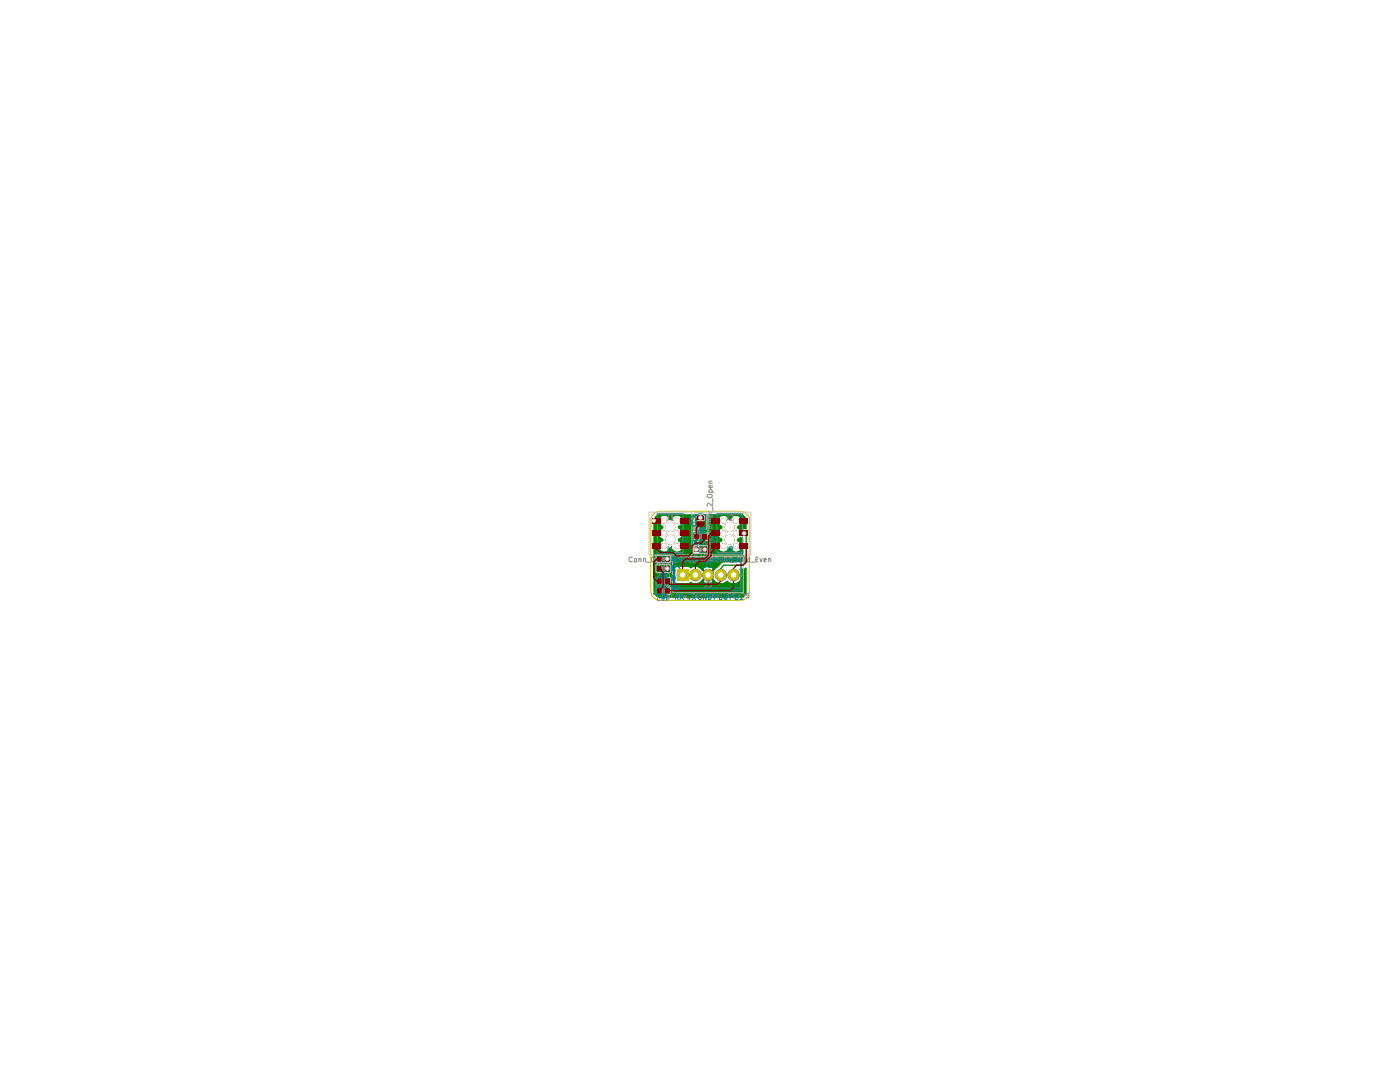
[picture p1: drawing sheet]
<svg xmlns="http://www.w3.org/2000/svg" width="279mm" height="216mm" viewBox="0 0 279 216" stroke-linecap="round" stroke-linejoin="round" font-family="sans-serif">
<g fill="none" stroke="#840084" stroke-width=".2">
<path d="M136 108.2h.5v1h-.5M136.1 108.7h.4M136.9 108.3l.3-.1 .3 .3v.5l-.3 .2-.3-.1M137.3 105.1l.2-.2 .4 .2v.6l-.4 .2a.6 .6 0 0 1-.2-.8zM137.8 109.2l.3-1 .3 1M137.9 108.9h.4M138.3 104.9h.5M138.5 104.9v1M138.7 108.2h.5v1M138.7 106.5v1M138.9 108.7h.3M139.7 107.1l-.5-.1v-.4l.5-.1v1"/>
<path d="M139.9 105.1l.2-.2 .3 .2v.6l-.2 .2-.3-.2zM140 108.7l-.4 .5M140.2 108.7h-.5l-.1-.4 .6-.1v1M140.5 107.1l-.4 .4M140.6 108.2h.5v1h-.5M140.7 107.1l-.5-.1-.1-.2 .2-.3h.4v1M140.7 108.7h.4M141.4 105l-.4-.1-.2 .2 .6 .8h-.6M141.4 108.2h.6M141.7 108.2v1M141.8 104.9v.8l.4 .2M142.3 108.2v1l.6-1v1"/>
<path d="M143.3 108.2v1"/>
</g>
<g fill="none" stroke="#840084" stroke-width=".34">
<path d="M130.5 118.4h.6M130.6 112v.1M131.1 117.6l-.3-.3v1.1M131.1 111l.6-.1a.67 .67 0 0 1 .2 .7 .67 .67 0 0 1-.5 .5l-.3-.1M131.7 118.4h.1M132.2 118.4h.6M132.4 110.9v1.2l.7-1.2v1.2M132.8 117.6l-.3-.3v1.1M133.7 110.9v1.2M134.1 117.3l.4 1.1 .4-1.1M135.1 110.9h.5l.2 .3v.6l-.2 .2h-.6v-.4h.3M135.2 117.3h.6v1.1h-.6"/>
<path d="M135.5 117.8h.3M136.3 110.9v1.2l.7-1.2v1.2M136.7 117.9l-.4 .5M137 117.9l-.6-.1-.1-.4 .2-.1h.5v1.1M137.6 110.9v1.2M138.5 111.5l-.4 .6M138.8 111.5l-.6-.1-.1-.3 .2-.2h.5v1.2M139.3 110.9h.6v1.2h-.6M139.4 117.3h-.6l-.1 .3 .7 .8h-.7M139.4 111.4h.5M139.9 117.4l.1-.1a.6 .6 0 0 1 .6 .5 .6 .6 0 0 1-.4 .6l-.3-.2zM140.4 110.9h.6v1.2h-.6"/>
<path d="M140.5 111.4h.5M141.1 118.4h.1M141.6 110.9v1.2l.6-1.2v1.2M141.6 117.6v.8M141.9 117.2l.3 .8h-.7M142.8 117.3h.4l.1 .1v.8l-.2 .2a.75 .75 0 0 1-.3-1.1zM142.8 110.9v1.2M143.3 110.9h.5l.2 .3v.6l-.2 .2h-.5v-.4h.2M143.8 118.4h.1M144.6 110.9v1.2l.7-1.2v1.2M145.1 117.3h-.6l-.1 .1v.4l.7 .6h-.7M145.8 110.9h.5v1.2h-.5"/>
<path d="M146 111.4h.3M146.2 117.3h-.6l-.1 .3 .8 .8h-.8M146.7 117.4l.2-.1a.6 .6 0 0 1 .6 .5 .6 .6 0 0 1-.4 .6l-.4-.2zM148.2 111.5l-.5 .6M148.4 111.5l-.6-.1-.1-.3 .2-.2h.5v1.2M148.5 117.3h-.6l-.1 .3 .8 .8h-.8"/>
</g>
<g fill="#848400">
<path d="M135.1 113.6h2.2v2.2h-2.2z"/>
<circle cx="138.8" cy="114.7" r="1.14"/>
<circle cx="141.3" cy="114.7" r="1.14"/>
<circle cx="143.8" cy="114.7" r="1.14"/>
<circle cx="146.4" cy="114.7" r="1.14"/>
<circle cx="133.8" cy="105.2" r=".97"/>
<circle cx="133.8" cy="107.7" r=".97"/>
<circle cx="132.5" cy="103.9" r=".55"/>
<circle cx="132.5" cy="106.4" r=".55"/>
<circle cx="132.5" cy="109" r=".55"/>
<circle cx="135" cy="103.9" r=".55"/>
<circle cx="135" cy="106.4" r=".55"/>
<circle cx="135" cy="109" r=".55"/>
<circle cx="146.9" cy="109" r=".55"/>
<circle cx="146.9" cy="106.4" r=".55"/>
<circle cx="146.9" cy="103.9" r=".55"/>
<circle cx="144.4" cy="109" r=".55"/>
<circle cx="144.4" cy="106.4" r=".55"/>
<circle cx="144.4" cy="103.9" r=".55"/>
<circle cx="145.6" cy="107.7" r=".97"/>
<circle cx="145.6" cy="105.2" r=".97"/>
</g>
<path d="M130.5 103.9h.6v6.3l2.6 2.6M133.2 113.5h.5M133.7 112.8v4.5M135 111.5l-1.3 1.3M139.8 103.3h-.4l-.5 .4v5.9M140.6 110.9h.1M140.6 109.6v1.3M140.6 110.9l-.6 .6h-6.8M141.3 114.7v1.9l-.7 .7h-9.5M148.5 106.4h.4v5.8l-.7 .6h-3.8l-.6 .7v1.2" fill="none" stroke="#008400" stroke-width=".25"/>
<path d="M130.8 103.2l.7-.5h7.5l-.5 .5-.3 .6v5.2a1.05 1.05 0 0 0 .1 1.5 1.05 1.05 0 0 0 1.4 0 1.05 1.05 0 0 0 .1-1.5l-.1-4.7h.5a1.05 1.05 0 0 0 .5-1.6h7.2l.5 .2 .3 .3 .2 .6v1.7a.92 .92 0 0 0-1.1 .3l-.6-.4 .1-.4a1.09 1.09 0 0 0 .7-1.6l-.7-.6h-.7a1.06 1.06 0 0 0-.8 .9h-.3l-.6-.8a1.16 1.16 0 0 0-1.5 .5 1.16 1.16 0 0 0 .4 1.5l.3 .1v.4a1.13 1.13 0 0 0-.9 1.1 1.13 1.13 0 0 0 .9 1.1v.3a1.17 1.17 0 0 0-.6 2 1.17 1.17 0 0 0 2-.6h.3a1.15 1.15 0 0 0 1.6 .8 1.15 1.15 0 0 0 .6-1.6l-.8-.6v-.2l.6-.5 .4 .3v4.4l-.2 .2h-3.5l-.6 .2-2.4 2.5 .8 .8a1.8 1.8 0 0 0 2.9 .3 1.74 1.74 0 0 0 2.4 .1 1.74 1.74 0 0 0 .1-2.4h.9l.3-.3v4.8a1.14 1.14 0 0 1-.9 1.1h-16.5l-.7-.5-.3-.8v-4.2h4v2.2l.2 .5 2.8 .1 .4-.3 .4 .3a1.71 1.71 0 0 0 1.7-.6h.2a1.24 1.24 0 0 0 2.2 0l-1.1-1-1.1 1h-.2l1.1-1.1-1.1-1.2h.2l1.1 1 1.1-1a1.24 1.24 0 0 0-2.2 0h-.2a1.45 1.45 0 0 0-2.1-.3l-.5-.3h-2.2l-.5 .2-.2 .5h-4v-9.7l.1-.2h.8a1.08 1.08 0 0 0 .9 1.3v.3h-.3a1.22 1.22 0 0 0-.5 1.7l.8 .6v.2l-.3 .1a1.22 1.22 0 0 0-.5 1.6 1.17 1.17 0 0 0 1.2 .6 1.17 1.17 0 0 0 .9-.9h.4a1.17 1.17 0 0 0 1.9 .6 1.17 1.17 0 0 0-.5-2v-.3a1.13 1.13 0 0 0 .9-1.1 1.13 1.13 0 0 0-.9-1.1v-.4a1.13 1.13 0 0 0 .9-1.1 1.13 1.13 0 0 0-.9-1.1h-.7l-.6 .6-.1 .3h-.4a1.06 1.06 0 0 0-.7-.9l-.9 .1-.5 .5-.1 .4h-.8z" fill="#008400"/>
<path d="M130.8 103.2l.7-.5h7.5l-.5 .5-.3 .6v5.2a1.05 1.05 0 0 0 .1 1.5 1.05 1.05 0 0 0 1.4 0 1.05 1.05 0 0 0 .1-1.5l-.1-4.7h.5a1.05 1.05 0 0 0 .5-1.6h7.2l.5 .2 .3 .3 .2 .6v1.7a.92 .92 0 0 0-1.1 .3l-.6-.4 .1-.4a1.09 1.09 0 0 0 .7-1.6l-.7-.6h-.7a1.06 1.06 0 0 0-.8 .9h-.3l-.6-.8a1.16 1.16 0 0 0-1.5 .5 1.16 1.16 0 0 0 .4 1.5l.3 .1v.4a1.13 1.13 0 0 0-.9 1.1 1.13 1.13 0 0 0 .9 1.1v.3a1.17 1.17 0 0 0-.6 2 1.17 1.17 0 0 0 2-.6h.3a1.15 1.15 0 0 0 1.6 .8 1.15 1.15 0 0 0 .6-1.6l-.8-.6v-.2l.6-.5 .4 .3v4.4l-.2 .2h-3.5l-.6 .2-2.4 2.5 .8 .8a1.8 1.8 0 0 0 2.9 .3 1.74 1.74 0 0 0 2.4 .1 1.74 1.74 0 0 0 .1-2.4h.9l.3-.3v4.8a1.14 1.14 0 0 1-.9 1.1h-16.5l-.7-.5-.3-.8v-4.2h4v2.2l.2 .5 2.8 .1 .4-.3 .4 .3a1.71 1.71 0 0 0 1.7-.6h.2a1.24 1.24 0 0 0 2.2 0l-1.1-1-1.1 1h-.2l1.1-1.1-1.1-1.2h.2l1.1 1 1.1-1a1.24 1.24 0 0 0-2.2 0h-.2a1.45 1.45 0 0 0-2.1-.3l-.5-.3h-2.2l-.5 .2-.2 .5h-4v-9.7l.1-.2h.8a1.08 1.08 0 0 0 .9 1.3v.3h-.3a1.22 1.22 0 0 0-.5 1.7l.8 .6v.2l-.3 .1a1.22 1.22 0 0 0-.5 1.6 1.17 1.17 0 0 0 1.2 .6 1.17 1.17 0 0 0 .9-.9h.4a1.17 1.17 0 0 0 1.9 .6 1.17 1.17 0 0 0-.5-2v-.3a1.13 1.13 0 0 0 .9-1.1 1.13 1.13 0 0 0-.9-1.1v-.4a1.13 1.13 0 0 0 .9-1.1 1.13 1.13 0 0 0-.9-1.1h-.7l-.6 .6-.1 .3h-.4a1.06 1.06 0 0 0-.7-.9l-.9 .1-.5 .5-.1 .4h-.8z" fill="none" stroke="#008400" stroke-width=".25"/>
<path d="M129.9 117.9a1.91 1.91 0 0 0 1.9 1.9M129.9 103.9v14M131.7 102h16M131.7 119.8h16M131.8 102a1.91 1.91 0 0 0-1.9 1.9M147.7 102a1.91 1.91 0 0 1 1.9 1.9M149.5 103.9v14M149.6 117.9a1.91 1.91 0 0 1-1.9 1.9" fill="none" stroke="#c2c200" stroke-width=".2"/>
<g fill="none" stroke="#848484" stroke-width=".2">
<path d="M141.3 98.6h.7l.2 .5a.6 .6 0 0 1-1.1 0zM141.5 98.2h1M141.5 96.4h.7M141.6 98.2l-.1-.3 .1-.2h.4l.2 .2-.1 .3M142.1 96.9l.1 .3-.2 .2h-.4l-.1-.4 .2-.1 .1 .5M142.2 96h-.6v.4M142.2 99.5v.7M126.2 111.2h-.5l-.1 .1v.6l.1 .2 .5-.1M126.6 111.6l.1-.2 .3 .1v.6l-.4-.1zM127.5 111.6l.2-.2 .2 .2v.5M127.5 111.4v.7M128.4 111.6l.1-.2 .4 .2v.5"/>
<path d="M128.4 111.4v.7M129 112.2h.8M130.1 111.2h.4l.1 .1-.1 .8h-.4l-.1-.2zM131 111.2h.5l.1 .2-.7 .7h.7M131.1 112.5l.6-.1v.3l-.6 .8h.6M131.1 114.5l.4-.2 .2 .3-.6 .7h.6M131.2 116.8v1.1h.5M131.2 118.8v1h.5M131.2 103.5l.7 .4-.7 .4M131.2 102.6h5.1v7.6h-5.1zM131.6 111.2h1.6v.7h-1.6zM131.6 113h1.6v.9h-1.6z"/>
<path d="M131.6 115.9l.3-.3h1.3v.8h-1.6zM131.6 117.8l.3-.3h1.3v.8h-1.6zM131.9 111.4l.5 .7M132.1 112.5l.5-.1 .1 .2-.6 .9h.6M132.1 114.5l.4-.2 .2 .3-.6 .7h.6M132.1 117.3h.3M132.1 119.3h.3M132.1 115.8l.3 .1-.1 .3h-.2zM132.1 117.7l.3 .1-.2 .3zM132.1 111.5h.3v-.1h-.3v.4M132.1 113.5l.3-.2-.3-.1v.5M132.2 111.5l.2 .3"/>
<path d="M132.2 113.5l.2 .2M132.4 111.4l-.5 .7M132.5 117.7h.2v.4h-.2M132.5 113.2h.2v.5h-.2M132.5 115.9l.1-.1 .1 .1-.2 .3h.2M132.5 111.4h.2v.1l-.2 .3h.2M132.6 116.8h-.5v1.1h.5M132.6 118.8h-.5v1h.5M132.8 111.2h.4l.1 .1-.1 .8h-.4v-.2zM133 116.8l.5 .3v.5l-.2 .3h-.3zM133 118.8h.3l.2 .2v.5l-.3 .3h-.2zM133.2 112.4l.4 .2v.6l-.3 .3-.3-.5z"/>
<path d="M133.2 114.4l.1-.1 .3 .3v.5l-.2 .2a.52 .52 0 0 1-.4-.4 .52 .52 0 0 1 .2-.5zM133.4 102.8v.8l-.1 .2h-.2M133.6 118.4h-.5a.36 .36 0 0 0 0 .4 .36 .36 0 0 0 .4 .1v.4h-.5M133.6 111.2h.7l-.4 .3 .4 .2-.1 .4-.6-.1M133.9 103.1l.3-.3v1M133.9 103.8h.5M134.4 118.7l-.4 .1v.4l.4 .1M134.4 112.2h.8M134.7 111.6h13.1v6.3h-12.6l-.5-.6zM134.7 112h13.1M134.7 117.3h13.1M134.9 118.7v.6"/>
<path d="M135.2 118.7h-.2l-.1 .2M135.5 119l.5-.1-.1-.2-.4 .1v.4l.4 .1M135.5 111.2h.6v.8h-.6zM136.3 118.7l.2 .6 .1-.4 .2 .4 .3-.6M136.9 111.2v.9h-.3l-.1-.5 .1-.2 .3 .1M136.9 113.9l-1.5 1.5M137 114l-1.5 1.6M137.2 119.5h.7M137.8 111.2v.9h-.4v-.6h.4M137.9 111.2h-.4l-.2 .4 .2 .5 .4-.1M138 118.4h.6M138.1 112.2h.8"/>
<path d="M138.3 111.6l.2-.2 .3 .1v.6l-.5-.1zM138.3 118.4v.9M138.7 107.9v1.1h.5M138.8 110.5l-.2 .7h.6M138.9 119l.5-.1v-.2l-.5 .1v.5h.5M139 109.2h1.6v.9h-1.6zM139 110.8v.7M139.3 111.6l.1-.2 .3 .1v.6M139.3 106.7h1.3v.8h-1.6v-.5zM139.3 111.4v.7M139.4 110.5h.7l-.4 1M139.4 113.9l-1.5 1.5"/>
<path d="M139.5 111.2h-.4v.9h.4M139.5 108.5h.3M139.5 114l-1.5 1.6M139.6 106.9l.1 .1v.3h-.1zM139.6 109.7h.1v-.3h-.1v.5M139.7 109.7v.2M139.8 118.7v.6M139.9 111.4l.2 .7 .3-.7M139.9 107.1l.2-.2v.4M139.9 109.6l.2-.2v.5M139.9 107.3h.3M139.9 109.9h.3"/>
<path d="M140 107.9h-.5v1.1h.5M140.1 118.7h-.2l-.1 .2M140.2 111.6l.1-.2 .3 .2v.5M140.2 111.4v.7M140.4 107.9a.59 .59 0 0 1 .5 .4 .59 .59 0 0 1-.1 .7h-.4zM140.4 118.8l.4-.1v.6M140.4 118.7v.6M140.5 110.7l.2-.2a.63 .63 0 0 1 .2 1l-.4-.1zM140.7 111.8l.4-.1v-.3l-.4 .1v.6h.4M140.8 118.8l.4-.1 .1 .6M140.9 112.2h.7M141 116.2v.7l-.5 .3"/>
<path d="M141.1 106.8h.8l.3 .4M141.1 109h1.1M141.2 111.3l-.1 .4 .2 .2 .3-.1 .1-.5h.4v.6M141.3 116.2h.6l-.3 .4 .3 .1v.4h-.6M141.5 110.6l.1-.2h.4l.2 .3-.1 .2h-.5zM141.5 107.4l.1 .3M141.5 102l.1 .4M141.5 107.7h.7M141.5 105.9h.7M141.5 105.4h.7M141.5 104.1h1M141.5 102.4h.7"/>
<path d="M141.6 109l-.1 .3 .1 .3 .5-.1v-.5M141.6 104.1v-.5h.5v.5M141.6 111.6l.1-.2 .3 .1v.6M141.6 111.4v.7M141.7 118.4h.1M141.7 118.7v.6M141.8 111.3l.2-.1a.47 .47 0 0 1 .4 .4 .47 .47 0 0 1-.4 .5l-.2-.2zM142 113.9l-1.5 1.5M142.1 108.2l.1 .3-.2 .1h-.4l-.1-.3 .2-.2 .1 .5M142.1 105.9l.1 .3-.2 .1h-.5M142.1 102.8v.4h-.5l-.1-.3 .2-.1 .1 .4M142.1 114l-1.6 1.6"/>
<path d="M142.2 109.8l-.1 .2h-1M142.2 105h-.6l-.1 .2 .1 .2M142.2 104.6h-.6l-.1 .1 .1 .3M142.2 100.4v.6l-.7-.6-.4 .2 .1 .4M142.2 118.8h.5v.5M142.2 101.2v.7M142.2 118.7v.6M142.7 111.2h.6v.1l-.6 .8h.6M143.1 118.7l.5 .1v.5h-.5v-.3l.5-.1M143.1 102.6h5.1v7.6h-5.1zM143.1 103.5l.6 .4-.6 .4M143.7 111.4l.5 .7"/>
<path d="M144 118.4v.8l.2 .1M144.2 111.4l-.5 .7M144.4 119.5h.7M144.5 113.9l-1.5 1.5M144.6 111.2h.1a.47 .47 0 0 1 .4 .4 .47 .47 0 0 1-.4 .5l-.2-.3zM144.6 114l-1.5 1.6M145.3 102.8v.7l-.2 .3h-.2M145.4 118.4a.51 .51 0 0 1 .5 .3 .51 .51 0 0 1-.2 .6h-.3l-.1-.2zM145.5 111.2h.5l-.3 .3 .3 .2v.4l-.5-.1M145.7 102.9h.5v.3l-.6 .6h.6M146.2 118.6l.3-.2v.9M146.2 112.2h.8"/>
<path d="M146.2 119.3h.6M147.1 113.9l-1.6 1.5M147.1 114l-1.5 1.6M147.1 118.7l.6 .6M147.2 111.2h.6l-.1 .9-.5-.1zM147.7 118.7l-.6 .6M148 118.5l.2-.1a.47 .47 0 0 1 .4 .4 .47 .47 0 0 1-.4 .5l-.2-.2zM148.7 111.2v.9h-.4l-.1-.5 .2-.2 .3 .1M149.4 118.4h-.4l-.1 .4 .4-.1 .2 .2-.1 .4-.5-.1M149.6 111.2v.9h-.3l-.1-.5 .1-.2 .3 .1M149.9 112.2h.7M150.9 111.6h.3"/>
<path d="M151.3 111.2h-.4v.9h.4M151.6 111.4l.3 .7 .2-.7M152.5 111.8l.5-.1-.2-.3-.3 .1v.6h.4M153.4 111.6l.1-.2 .3 .2v.5M153.4 111.4v.7"/>
<circle cx="136.3" cy="114.8" r="1.14"/>
<circle cx="138.8" cy="114.8" r="1.14"/>
<circle cx="141.3" cy="114.8" r="1.14"/>
<circle cx="143.9" cy="114.8" r="1.14"/>
<circle cx="146.4" cy="114.8" r="1.14"/>
</g>
<path d="M129.5 102.2h8.6v8.5h-8.6zM130.9 110.8h3v1.5h-3zM130.9 112.7h3v1.5h-3zM130.9 115.2h3v1.6h-3zM130.9 117.2h3v1.4h-3zM134.2 111.1h14.1v7.2h-14.1zM138.5 102.3h2.6v3.3h-2.6zM141.3 102.2h8.6v8.5h-8.6zM141.3 106.3h-3v1.6h3M141.3 108.9h-3v1.5h3" fill="none" stroke="#c2c2c2" stroke-width=".2"/>
<g fill="#840000">
<path d="M138.6 106.7h.8v.7l-.1 .2-.7-.1z"/>
<path d="M138.7 109.1l.7 .1v.9h-.8z"/>
<path d="M140.2 109.3l.2-.2h.5l.2 .2v.7l-.2 .1h-.5l-.2-.1z"/>
<path d="M135.8 105.9h1.8v1h-1.8z"/>
<path d="M135.8 108.5h1.8v1h-1.8z"/>
<path d="M132.8 115.6h.8v.7l-.2 .2-.6-.1z"/>
<path d="M131.3 115.5l.7 .1v.8l-.7 .1-.2-.2v-.6z"/>
<path d="M131.1 117.5l.8-.1 .1 .9-.8 .1z"/>
<path d="M132.8 117.5h.8l-.1 .9-.7-.1z"/>
<path d="M132.8 111.1l.8 .1-.1 .8h-.7z"/>
<path d="M131.1 111.2l.8-.1v.9l-.8-.1z"/>
<path d="M131.1 113l.7-.1 .2 .2v.6l-.2 .3-.7-.1z"/>
<path d="M132.9 112.9l.7 .1v.9h-.8z"/>
<path d="M130 103.4h1.8v1h-1.8z"/>
<path d="M130 105.9h1.8v1h-1.8z"/>
<path d="M130 108.5h1.8v1h-1.8z"/>
<path d="M135.8 103.4h1.8v1h-1.8z"/>
<path d="M140.2 106.7l.7-.1 .2 .2v.6l-.2 .2h-.6l-.2-.2z"/>
<path d="M147.6 108.5h1.7v1h-1.7z"/>
<path d="M147.6 105.9h1.7v1h-1.7z"/>
<path d="M147.6 103.4h1.7v1h-1.7z"/>
<path d="M141.8 108.5h1.8v1h-1.8z"/>
<path d="M141.8 105.9h1.8v1h-1.8z"/>
<path d="M141.8 103.4h1.8v1h-1.8z"/>
</g>
<g fill="none" stroke="#008484" stroke-width=".2">
<path d="M131.1 103.2v-.7h5.4v.7M131.1 109.6v.8h5.4v-.8M131.7 119.2h.2l.1-.2-.3-.1v.6M131.7 114.8h.2l.1-.3-.3-.1v.6M132.2 111h.4M132.2 112.1h.4M132.2 114h.4M132.2 112.9h.4M132.3 119.2h.2l.1-.2-.3-.1v.6h.2l.1-.3h-.1M132.3 114.7h.2l.1-.2-.3-.1v.6h.2l.1-.2-.1-.1M132.9 119.1l.2-.2v.6M132.9 119.5h.3"/>
<path d="M133 114.4h.1l.1 .3-.1 .3-.2-.1zM133.2 117.2h-2.3v1.4h2.3M133.2 115.2h-2.3v1.6h2.3M133.3 109v.8l-.1 .3h-.3M133.8 109.4l.2-.4v1.1M133.8 110.1h.5M134.2 116.7h.2l.3 .2 .1 .4-.3 .4h-.3zM134.2 114.8h.2l.4 .4-.4 .6h-.2zM134.2 111.5h.4l.2-.3-.6-.2v1M134.2 113.5l.5-.1 .1-.3-.3-.2h-.3v1M134.4 117.3v.8h.5M134.4 111.5l.4 .5"/>
<path d="M134.4 113.5l.4 .4M134.6 111.6h13.3v6.3h-13.3zM134.6 112h13.3M134.6 117.3h13.3M134.8 119.1h.5l.1-.4-.6-.1v1M135 119.1l.4 .5M135.1 116.7h.6l-.3 .4 .3 .2-.1 .4-.5-.1M135.1 114.9l.4-.1 .2 .2-.6 .8h.6M135.1 111.1l.4-.1 .2 .2-.6 .8h.6M135.1 112.9h.6l-.3 .4 .3 .2-.1 .4-.5-.1M135.7 118.6l.7 1M136.3 108.1a.55 .55 0 0 1 .9 0v.4h-.9z"/>
<path d="M136.4 118.6l-.7 1M137.2 107.3h-.9l.3 .2M137.2 106.9v.6M137.3 118.6h.6M137.6 104.7h.7l.2 .2v.3M137.6 118.6v1M138 108.1h.4M138.1 104.3l-.1-.6h-.3l-.1 .6h.9M138.2 118.6l.6 1M138.2 108.1v.6M138.5 103h-.9l.2 .3M138.5 102.8v.5"/>
<path d="M138.6 108.4l.3-.1-.1-.2h-.2v.6M138.7 108.4l.2 .3M138.8 118.6l-.6 1M138.8 103.2v1.4M138.9 104.7a.7 .7 0 0 0 .7 .7M139.1 105.5h-.4v.3h.4l-.1 .3-.3-.1M139.1 108.1v.6M139.2 105.5l.2 .6 .3-.6M139.5 110.1h.5M139.5 109.1h.5M139.5 105.3h.6M139.8 108.2a.28 .28 0 0 0-.3 .1 .28 .28 0 0 0 .1 .4l.2-.1"/>
<path d="M139.8 105.5h.3l.1 .2-.1 .4h-.3zM139.9 118.7a.46 .46 0 0 0-.6 .5 .46 .46 0 0 0 .7 .3v-.3h-.3M140.1 108.1v.6M140.1 102.5a1 1 0 0 0-1.2 .5v.2M140.2 102.5a.7 .7 0 0 1 .7 .7M140.2 108.3l.2 .4M140.4 108.1l-.3 .3M140.6 106.3h-2.3v1.6h2.3M140.7 108.1v.6h.2M140.8 105.6l-.3-.1-.1 .2 .1 .4 .3-.1M140.8 103.2v1.4M140.9 104.7a.7 .7 0 0 1-.7 .7"/>
<path d="M140.9 118.6v1l-.5-1v1M141 112.3v.6l-.5 .4M141.1 108.3h.2M141.3 112.3h.6l-.3 .3 .3 .2v.4h-.6M141.4 118.6a.52 .52 0 0 1 .6 .5 .52 .52 0 0 1-.6 .5zM141.4 108.1h-.3v.6h.3M142.5 108.5v-.5l-.3-.1-.2 .6h1M142.6 119.1h.5l.1-.3-.6-.2v1M142.9 109.6v.8h5.3v-.8M142.9 103.2v-.7h5.3v.7M143 107.3h-1l.2 .2M143 107.9l-.5 .3"/>
<path d="M143 106.9v.6M143.6 119.1h.3l.2-.3-.2-.2h-.3v1l.5-.1v-.3l-.2-.1M144.6 118.7l.2-.1a.54 .54 0 0 1 .3 .5 .54 .54 0 0 1-.3 .5l-.2-.1-.1-.3zM145.3 109v.8l-.2 .3h-.2M145.7 119.1h.5l.1-.4-.6-.1v1M145.7 109.2l.1-.2h.2l.2 .2v.4l-.6 .5h.6M146.7 119.1h.4l.1-.4-.5-.1v1h.4l.2-.3-.2-.2M147.7 118.9h.1l.2-.3v1M147.7 119.6h.5"/>
</g>
<g fill="#840084">
<path d="M140.2 109.3l.2-.2h.5l.2 .2v.7l-.2 .1h-.5l-.2-.1z"/>
<path d="M141.8 108.5h1.8v1h-1.8z"/>
<path d="M135.1 113.6h2.2v2.2h-2.2z"/>
<path d="M132.8 115.6h.8v.7l-.2 .2-.6-.1z"/>
<path d="M132.8 117.5h.8l-.1 .9-.7-.1z"/>
<path d="M131.3 115.5l.7 .1v.8l-.7 .1-.2-.2v-.6z"/>
<path d="M131.1 117.5l.8-.1 .1 .9-.8 .1z"/>
<path d="M132.8 111.1l.8 .1-.1 .8h-.7z"/>
<path d="M131.1 111.2l.8-.1v.9l-.8-.1z"/>
<path d="M131.1 113l.7-.1 .2 .2v.6l-.2 .3-.7-.1z"/>
<path d="M132.9 112.9l.7 .1v.9h-.8z"/>
<path d="M138.6 106.7h.8v.7l-.1 .2-.7-.1z"/>
<path d="M140.2 106.7l.7-.1 .2 .2v.6l-.2 .2h-.6l-.2-.2z"/>
<path d="M138.7 109.1l.7 .1v.9h-.8z"/>
<path d="M139 104.1h1.5v.8l-.3 .2-1-.1-.2-.4z"/>
<path d="M139.2 102.9h1.2l.1 .2v.7h-1.5v-.6z"/>
<path d="M135.8 103.4h1.8v1h-1.8z"/>
<path d="M135.8 105.9h1.8v1h-1.8z"/>
<path d="M135.8 108.5h1.8v1h-1.8z"/>
<path d="M130 108.5h1.8v1h-1.8z"/>
<path d="M130 103.4h1.8v1h-1.8z"/>
<path d="M130 105.9h1.8v1h-1.8z"/>
<path d="M147.6 108.5h1.7v1h-1.7z"/>
<path d="M147.6 105.9h1.7v1h-1.7z"/>
<path d="M147.6 103.4h1.7v1h-1.7z"/>
<path d="M141.8 105.9h1.8v1h-1.8z"/>
<path d="M141.8 103.4h1.8v1h-1.8z"/>
<circle cx="141.3" cy="114.7" r="1.14"/>
<circle cx="143.8" cy="114.7" r="1.14"/>
<circle cx="146.4" cy="114.7" r="1.14"/>
<circle cx="138.8" cy="114.7" r="1.14"/>
<circle cx="133.8" cy="107.7" r=".97"/>
<circle cx="132.5" cy="106.4" r=".55"/>
<circle cx="132.5" cy="109" r=".55"/>
<circle cx="135" cy="106.4" r=".55"/>
<circle cx="135" cy="109" r=".55"/>
<circle cx="133.8" cy="105.2" r=".97"/>
<circle cx="132.5" cy="103.9" r=".55"/>
<circle cx="135" cy="103.9" r=".55"/>
<circle cx="146.9" cy="109" r=".55"/>
<circle cx="146.9" cy="106.4" r=".55"/>
<circle cx="146.9" cy="103.9" r=".55"/>
<circle cx="144.4" cy="109" r=".55"/>
<circle cx="144.4" cy="106.4" r=".55"/>
<circle cx="144.4" cy="103.9" r=".55"/>
<circle cx="145.6" cy="107.7" r=".97"/>
<circle cx="145.6" cy="105.2" r=".97"/>
</g>
<g fill="none" stroke="#840000" stroke-width=".25">
<path d="M130.5 103.9h.4M131.6 111.5h-.5l-.6 .7v3.1l.6 .7h.5M131.6 113.5l.7 .7v2.9l-.7 .8M136.7 106.4h.1M139 107.1h.1M139.8 104.6l-.8 .7v1.8M140.5 107.1v.7l-.5 .6h-1.2l-.7 .6v1.2l-.6 .7h-2.5l-.7-.7h-2.6l-.8-.8v-.4M142.7 106.4h-.8l-.5 .6v3.8l-.8 .7h-3.8l-.6 .7v2.5M142.7 109v.5l-.8 .7v.7l-1.1 1.1h-1.3l-.7 .8v1.9M143.8 114.7v1.3l-.6 .6h-9.5l-.5-.4v-.2M146.6 114.5l-.2 .2M148.2 106.4h.3"/>
<path d="M148.9 109h-.4l.4 .4v2.8l-.7 .6h-1.2l-.6 .7v3.8l-.7 .6h-12.5"/>
</g>
<g fill="#840000">
<path d="M138.6 106.7h.8v.7l-.1 .2-.7-.1z"/>
<path d="M140.2 106.7l.7-.1 .2 .2v.6l-.2 .2h-.6l-.2-.2z"/>
<path d="M138.7 109.1l.7 .1v.9h-.8z"/>
<path d="M140.2 109.3l.2-.2h.5l.2 .2v.7l-.2 .1h-.5l-.2-.1z"/>
<path d="M139 104.1h1.5v.8l-.3 .2-1-.1-.2-.4z"/>
<path d="M132.8 115.6h.8v.7l-.2 .2-.6-.1z"/>
<path d="M131.3 115.5l.7 .1v.8l-.7 .1-.2-.2v-.6z"/>
<path d="M131.1 117.5l.8-.1 .1 .9-.8 .1z"/>
<path d="M132.8 117.5h.8l-.1 .9-.7-.1z"/>
<path d="M132.8 111.1l.8 .1-.1 .8h-.7z"/>
<path d="M131.1 111.2l.8-.1v.9l-.8-.1z"/>
<path d="M131.1 113l.7-.1 .2 .2v.6l-.2 .3-.7-.1z"/>
<path d="M132.9 112.9l.7 .1v.9h-.8z"/>
<path d="M139.2 102.9h1.2l.1 .2v.7h-1.5v-.6z"/>
<path d="M130 103.4h1.8v1h-1.8z"/>
<path d="M130 105.9h1.8v1h-1.8z"/>
<path d="M130 108.5h1.8v1h-1.8z"/>
<path d="M135.8 103.4h1.8v1h-1.8z"/>
<path d="M135.8 105.9h1.8v1h-1.8z"/>
<path d="M135.8 108.5h1.8v1h-1.8z"/>
<path d="M147.6 108.5h1.7v1h-1.7z"/>
<path d="M147.6 105.9h1.7v1h-1.7z"/>
<path d="M147.6 103.4h1.7v1h-1.7z"/>
<path d="M141.8 108.5h1.8v1h-1.8z"/>
<path d="M141.8 105.9h1.8v1h-1.8z"/>
<path d="M141.8 103.4h1.8v1h-1.8z"/>
</g>
<g fill="#c2c200">
<path d="M135.1 113.6h2.2v2.2h-2.2z"/>
<circle cx="138.8" cy="114.7" r="1.14"/>
<circle cx="141.3" cy="114.7" r="1.14"/>
<circle cx="143.8" cy="114.7" r="1.14"/>
<circle cx="146.4" cy="114.7" r="1.14"/>
<circle cx="133.8" cy="105.2" r=".97"/>
<circle cx="133.8" cy="107.7" r=".97"/>
<circle cx="132.5" cy="103.9" r=".55"/>
<circle cx="132.5" cy="106.4" r=".55"/>
<circle cx="132.5" cy="109" r=".55"/>
<circle cx="135" cy="103.9" r=".55"/>
<circle cx="135" cy="106.4" r=".55"/>
<circle cx="135" cy="109" r=".55"/>
<circle cx="146.9" cy="109" r=".55"/>
<circle cx="146.9" cy="106.4" r=".55"/>
<circle cx="146.9" cy="103.9" r=".55"/>
<circle cx="144.4" cy="109" r=".55"/>
<circle cx="144.4" cy="106.4" r=".55"/>
<circle cx="144.4" cy="103.9" r=".55"/>
<circle cx="145.6" cy="107.7" r=".97"/>
<circle cx="145.6" cy="105.2" r=".97"/>
</g>
<g fill="#c2c2c2">
<circle cx="148.5" cy="106.4" r=".47"/>
<circle cx="130.5" cy="103.9" r=".47"/>
<circle cx="140.6" cy="109.6" r=".47"/>
<circle cx="133.2" cy="113.5" r=".47"/>
<circle cx="133.2" cy="111.5" r=".47"/>
<circle cx="138.9" cy="109.6" r=".47"/>
<circle cx="139.8" cy="103.3" r=".47"/>
</g>
<g fill="#fff">
<path d="M148.4 106.2h.2l.1 .2-.1 .2h-.2l-.1-.2z"/>
<path d="M130.4 103.7h.2l.1 .2-.1 .2h-.2l-.1-.2z"/>
<path d="M140.5 109.5h.2l.1 .1-.1 .2h-.2l-.1-.2z"/>
<path d="M133.1 113.3h.2l.1 .2-.1 .1h-.2l-.1-.1z"/>
<path d="M133.1 111.3h.2l.1 .2-.1 .2h-.2l-.1-.2z"/>
<path d="M138.8 109.5h.2l.1 .1-.1 .2h-.2l-.1-.2z"/>
<path d="M139.7 103.1h.2l.1 .2-.1 .2h-.2l-.1-.2z"/>
<circle cx="133.8" cy="105.2" r=".97"/>
<circle cx="133.8" cy="107.7" r=".97"/>
<circle cx="132.5" cy="103.9" r=".55"/>
<circle cx="132.5" cy="106.4" r=".55"/>
<circle cx="132.5" cy="109" r=".55"/>
<circle cx="135" cy="103.9" r=".55"/>
<circle cx="135" cy="106.4" r=".55"/>
<circle cx="135" cy="109" r=".55"/>
<circle cx="144.4" cy="103.9" r=".55"/>
<circle cx="146.9" cy="109" r=".55"/>
<circle cx="146.9" cy="106.4" r=".55"/>
<circle cx="146.9" cy="103.9" r=".55"/>
<circle cx="144.4" cy="109" r=".55"/>
<circle cx="144.4" cy="106.4" r=".55"/>
<circle cx="145.6" cy="107.7" r=".97"/>
<circle cx="145.6" cy="105.2" r=".97"/>
<circle cx="136.2" cy="114.7" r=".55"/>
<circle cx="138.8" cy="114.7" r=".55"/>
<circle cx="141.3" cy="114.7" r=".55"/>
<circle cx="143.8" cy="114.7" r=".55"/>
<circle cx="146.4" cy="114.7" r=".55"/>
</g>
</svg>
